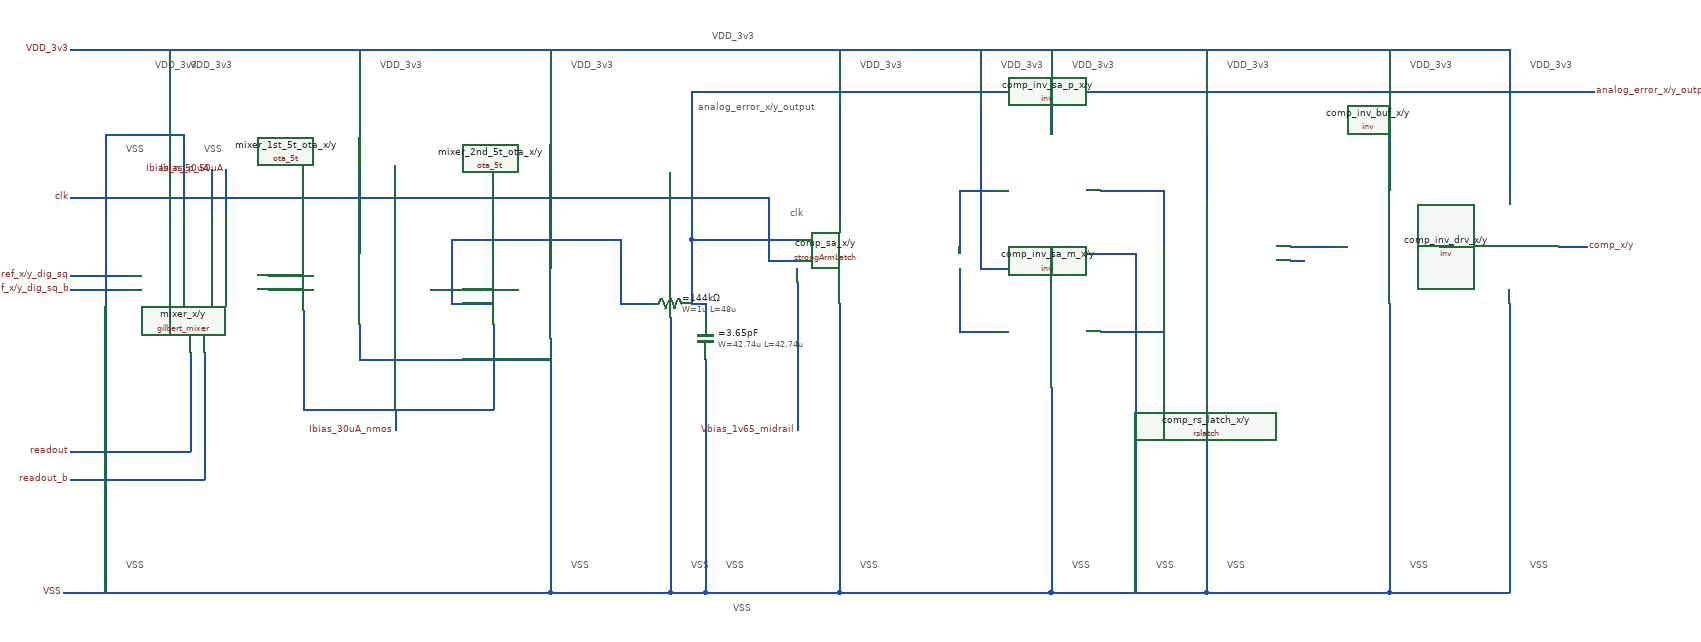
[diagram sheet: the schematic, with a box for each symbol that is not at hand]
v {xschem version=3.4.8RC file_version=1.3}
G {}
K {}
V {}
S {}
F {}
E {}
T {VSS} 800 110 1 0 0.4 0.4 {}
T {VSS} 850 110 1 0 0.4 0.4 {}
T {VSS} 630 110 1 0 0.4 0.4 {}
T {VSS} 1040 110 1 0 0.4 0.4 {}
T {VSS} 1340 110 1 0 0.4 0.4 {}
T {VSS} 1460 110 1 0 0.4 0.4 {}
T {VSS} 1560 110 1 0 0.4 0.4 {}
T {VSS} 1820 110 1 0 0.4 0.4 {}
T {VSS} 1990 110 1 0 0.4 0.4 {}
T {VDD_3v3} 1990 -600 1 0 0.4 0.4 {}
T {VDD_3v3} 1820 -600 1 0 0.4 0.4 {}
T {VDD_3v3} 1560 -600 1 0 0.4 0.4 {}
T {VDD_3v3} 1340 -600 1 0 0.4 0.4 {}
T {VDD_3v3} 1240 -600 1 0 0.4 0.4 {}
T {VDD_3v3} 630 -600 1 0 0.4 0.4 {}
T {VDD_3v3} 360 -600 1 0 0.4 0.4 {}
T {VDD_3v3} 90 -600 1 0 0.4 0.4 {}
T {VDD_3v3} 40 -600 1 0 0.4 0.4 {}
T {VDD_3v3} 830 -640 0 0 0.4 0.4 {}
T {VSS} 110 -480 1 0 0.4 0.4 {}
T {clk} 940 -390 1 0 0.4 0.4 {}
T {VDD_3v3} 1040 -600 1 0 0.4 0.4 {}
T {analog_error_x/y_output} 810 -540 0 0 0.4 0.4 {}
T {VSS} 860 170 0 0 0.4 0.4 {}
T {VSS} 0 110 1 0 0.4 0.4 {}
T {VSS} 0 -480 1 0 0.4 0.4 {}
N 200 -270 250 -270 {lab=#net1}
N 200 -290 250 -290 {lab=#net2}
N 430 -270 520 -270 {lab=#net3}
N 460 -250 520 -250 {lab=#net4}
N 60 -610 60 -380 {lab=VDD_3v3}
N 330 -610 330 -320 {lab=VDD_3v3}
N 600 -610 600 -300 {lab=VDD_3v3}
N 460 -340 460 -250 {lab=#net4}
N 460 -340 700 -340 {lab=#net4}
N 700 -340 700 -250 {lab=#net4}
N 700 -250 740 -250 {lab=#net4}
N 330 -220 330 -170 {lab=VSS}
N 800 -340 800 -250 {lab=analog_error_x/y_output}
N 910 -310 950 -310 {lab=clk}
N 1180 -300 1180 -210 {lab=#net5}
N 1180 -210 1230 -210 {lab=#net5}
N 1180 -410 1180 -320 {lab=#net6}
N 1180 -410 1230 -410 {lab=#net6}
N 1310 -300 1310 -290 {lab=VDD_3v3}
N 1210 -300 1310 -300 {lab=VDD_3v3}
N 1310 -330 1310 -320 {lab=VSS}
N 1310 -320 1430 -320 {lab=VSS}
N 1380 -210 1470 -210 {lab=#net7}
N 1470 -310 1470 -210 {lab=#net7}
N 1380 -410 1470 -410 {lab=#net8}
N 1470 -410 1470 -330 {lab=#net8}
N 1530 -610 1530 -390 {lab=VDD_3v3}
N 1210 -610 1210 -300 {lab=VDD_3v3}
N 1310 -610 1310 -490 {lab=VDD_3v3}
N 1650 -310 1670 -310 {lab=#net9}
N 1650 -330 1710 -330 {lab=#net10}
N 1790 -610 1790 -410 {lab=VDD_3v3}
N 1960 -610 1960 -410 {lab=VDD_3v3}
N 2030 -330 2070 -330 {lab=comp_x/y}
N 330 -170 600 -170 {lab=VSS}
N 800 -340 950 -340 {lab=analog_error_x/y_output}
N 910 -400 910 -310 {lab=clk}
N 120 -440 120 -380 {lab=Ibias_n_50uA}
N 140 -440 140 -380 {lab=Ibias_p_50uA}
N 800 -250 820 -250 {lab=analog_error_x/y_output}
N 820 -250 820 -230 {lab=analog_error_x/y_output}
N 380 -100 380 -70 {lab=Ibias_30uA_nmos}
N 250 -100 520 -100 {lab=Ibias_30uA_nmos}
N 600 160 770 160 {lab=VSS}
N 770 160 820 160 {lab=VSS}
N 820 160 870 160 {lab=VSS}
N 870 160 1010 160 {lab=VSS}
N 1790 160 1960 160 {lab=VSS}
N 1530 160 1790 160 {lab=VSS}
N 1310 160 1530 160 {lab=VSS}
N 1010 160 1310 160 {lab=VSS}
N 80 -490 80 -380 {lab=VSS}
N -30 -490 80 -490 {lab=VSS}
N -80 0 110 0 {lab=readout_b}
N -80 -40 90 -40 {lab=readout}
N -80 -270 0 -270 {lab=ref_x/y_dig_sq_b}
N -80 -290 0 -290 {lab=ref_x/y_dig_sq}
N -80 -610 1960 -610 {lab=VDD_3v3}
N -80 -400 910 -400 {lab=clk}
N 1010 -610 1010 -370 {lab=VDD_3v3}
N 800 -550 800 -340 {lab=analog_error_x/y_output}
N 800 -550 2080 -550 {lab=analog_error_x/y_output}
N 90 -180 90 -40 {lab=readout}
N 110 -180 110 0 {lab=readout_b}
N -30 -490 -30 160 {lab=VSS}
N -90 160 600 160 {lab=VSS}
N 1310 -130 1310 160 {lab=VSS}
N 1430 -320 1430 160 {lab=VSS}
N 1530 -250 1530 160 {lab=VSS}
N 1790 -250 1790 160 {lab=VSS}
N 1960 -250 1960 160 {lab=VSS}
N 820 -170 820 160 {lab=VSS}
N 1010 -250 1010 160 {lab=VSS}
N 950 -280 950 -70 {lab=Vbias_1v65_midrail}
N 770 -230 770 160 {lab=VSS}
N 520 -220 520 -100 {lab=Ibias_30uA_nmos}
N 250 -240 250 -100 {lab=Ibias_30uA_nmos}
N 600 -200 600 160 {lab=VSS}
N 1860 -330 1880 -330 {lab=#net11}
C {Analog/schematics/2_mixer/gilbert_mixer.sym} 100 -280 0 0 {name=mixer_x/y}
C {Analog/schematics/2_mixer/ota_5t.sym} 270 -220 0 0 {name=mixer_1st_5t_ota_x/y}
C {Analog/schematics/2_mixer/ota_5t.sym} 540 -200 0 0 {name=mixer_2nd_5t_ota_x/y}
C {Analog/schematics/3_comparator/strongArmLatch.sym} 1090 -320 0 0 {name=comp_sa_x/y}
C {Analog/schematics/3_comparator/inv.sym} 1230 -490 0 0 {name=comp_inv_sa_p_x/y}
C {Analog/schematics/3_comparator/inv.sym} 1230 -290 0 0 {name=comp_inv_sa_m_x/y}
C {Analog/schematics/3_comparator/rslatch.sym} 1570 -310 0 0 {name=comp_rs_latch_x/y}
C {Analog/schematics/3_comparator/inv.sym} 1710 -410 0 0 {name=comp_inv_buf_x/y}
C {Analog/schematics/3_comparator/inv.sym} 1880 -410 0 0 {name=comp_inv_drv_x/y}
C {lab_pin.sym} -80 -610 2 1 {name=p1 sig_type=std_logic lab=VDD_3v3}
C {lab_pin.sym} 120 -440 1 0 {name=p3 sig_type=std_logic lab=Ibias_n_50uA}
C {lab_pin.sym} 140 -440 1 0 {name=p4 sig_type=std_logic lab=Ibias_p_50uA}
C {lab_pin.sym} -80 -290 2 1 {name=p5 sig_type=std_logic lab=ref_x/y_dig_sq}
C {lab_pin.sym} -80 -270 2 1 {name=p6 sig_type=std_logic lab=ref_x/y_dig_sq_b}
C {lab_pin.sym} 380 -70 1 1 {name=p7 sig_type=std_logic lab=Ibias_30uA_nmos}
C {symbols/ppolyf_u_3k.sym} 770 -250 3 0 {name="=144kΩ"
W=1u
L=48u
model=ppolyf_u_3k
spiceprefix=r
m=1
}
C {symbols/cap_mim_analog.sym} 820 -200 0 0 {name="=3.65pF"
W=42.74u
L=42.74u
model="cap_mim_2f0
_m3m4_noshield"
spiceprefix=c
m=1}
C {noconn.sym} 1670 -310 2 0 {name=l15}
C {lab_pin.sym} 2070 -330 2 0 {name=p8 sig_type=std_logic lab=comp_x/y}
C {lab_pin.sym} -80 -400 2 1 {name=p9 sig_type=std_logic lab=clk}
C {lab_pin.sym} -80 -40 2 1 {name=p10 sig_type=std_logic lab=readout}
C {lab_pin.sym} -80 0 2 1 {name=p11 sig_type=std_logic lab=readout_b}
C {lab_pin.sym} 950 -70 1 1 {name=p13 sig_type=std_logic lab=Vbias_1v65_midrail}
C {lab_pin.sym} 2080 -550 2 0 {name=p19 sig_type=std_logic lab=analog_error_x/y_output}
C {lab_pin.sym} -90 160 2 1 {name=p2 sig_type=std_logic lab=VSS}
